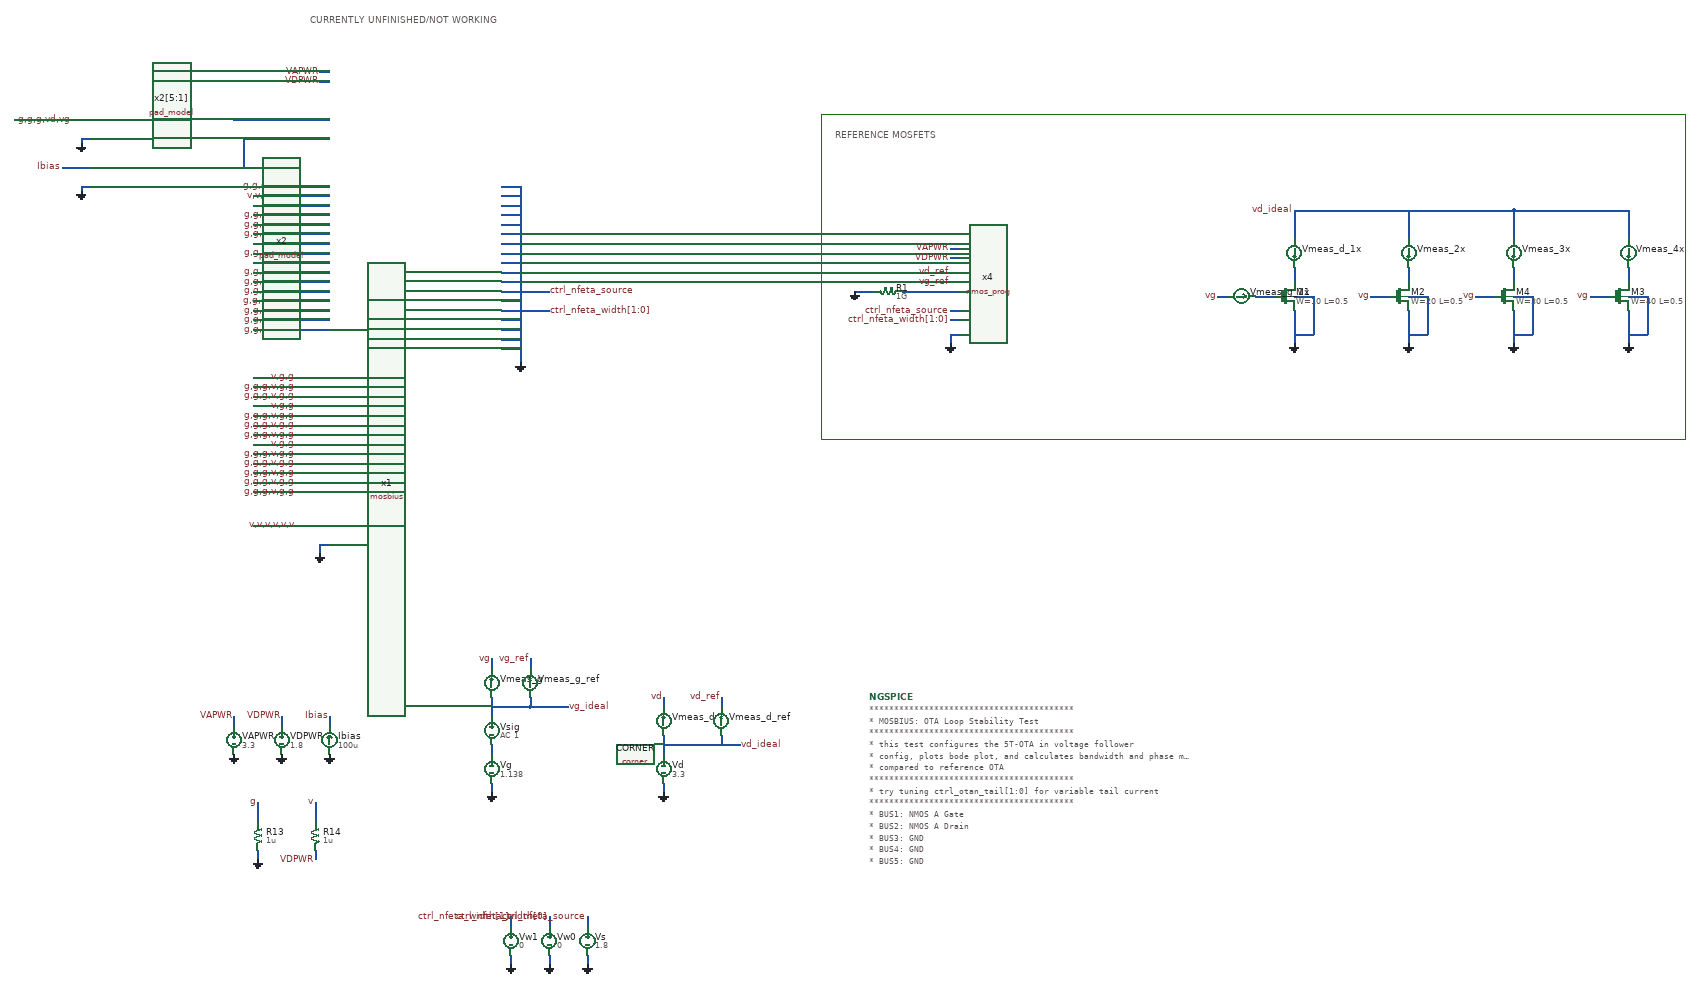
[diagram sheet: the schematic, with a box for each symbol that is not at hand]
v {xschem version=3.1.0 file_version=1.2
}
G {}
K {}
V {}
S {}
E {}
L 4 1330 -1160 1330 -480 {}
L 4 3140 -1160 3140 -480 {}
L 4 1330 -480 3140 -480 {}
L 4 1330 -1160 3140 -1160 {}
T {REFERENCE MOSFETS} 1360 -1130 0 0 0.4 0.4 {}
T {CURRENTLY UNFINISHED/NOT WORKING} 260 -1370 0 0 0.4 0.4 {}
N 100 100 100 120 {
lab=VAPWR}
N 200 100 200 120 {
lab=VDPWR}
N 280 -1230 300 -1230 {
lab=VDPWR}
N 280 -1250 300 -1250 {
lab=VAPWR}
N 280 -260 280 -240 {
lab=GND}
N 280 -260 300 -260 {
lab=GND}
N 300 100 300 120 {
lab=Ibias}
N 660 -970 700 -970 {
lab=GND}
N 660 -950 700 -950 {
lab=GND}
N 660 -930 700 -930 {
lab=GND}
N 660 -910 700 -910 {
lab=GND}
N 660 -890 700 -890 {
lab=GND}
N 660 -870 700 -870 {
lab=GND}
N 660 -850 700 -850 {
lab=GND}
N 660 -830 700 -830 {
lab=GND}
N 660 -810 700 -810 {
lab=GND}
N 660 -770 700 -770 {
lab=GND}
N 660 -730 700 -730 {
lab=GND}
N 660 -710 700 -710 {
lab=GND}
N 660 -690 700 -690 {
lab=GND}
N 660 -670 700 -670 {
lab=GND}
N 640 240 640 260 {
lab=GND}
N 660 -990 700 -990 {
lab=GND}
N 150 380 150 400 {
lab=GND}
N 150 280 150 320 {
lab=g}
N 270 280 270 320 {
lab=v}
N 270 380 270 400 {
lab=VDPWR}
N 140 -370 300 -370 {
lab=g,g,g,v,g,g}
N 140 -390 300 -390 {
lab=g,g,g,v,g,g}
N 140 -410 300 -410 {
lab=g,g,g,v,g,g}
N 140 -430 300 -430 {
lab=g,g,g,v,g,g}
N 140 -450 300 -450 {
lab=g,g,g,v,g,g}
N 140 -470 300 -470 {
lab=v,g,g}
N 140 -490 300 -490 {
lab=g,g,g,v,g,g}
N 140 -510 300 -510 {
lab=g,g,g,v,g,g}
N 140 -530 300 -530 {
lab=g,g,g,v,g,g}
N 140 -550 300 -550 {
lab=v,g,g}
N 140 -570 300 -570 {
lab=g,g,g,v,g,g}
N 140 -590 300 -590 {
lab=g,g,g,v,g,g}
N 140 -610 300 -610 {
lab=v,g,g}
N 140 -710 300 -710 {
lab=g,g,g,v,g,g}
N 140 -730 300 -730 {
lab=g,g,g,v,g,g}
N 140 -750 300 -750 {
lab=g,g,g,v,g,g}
N 140 -770 300 -770 {
lab=g,g,g,g,g,g}
N 140 -790 300 -790 {
lab=g,g,g,g,g,v}
N 140 -810 300 -810 {
lab=g,g,g,g,v,g}
N 140 -830 300 -830 {
lab=g,g,g,v,g,g}
N 140 -870 300 -870 {
lab=g,g,g,v,g,g}
N 140 -910 300 -910 {
lab=g,g,g,v,g,g}
N 140 -930 300 -930 {
lab=g,g,g,v,g,g}
N 140 -1010 300 -1010 {
lab=g,g,g,g,g,g}
N 140 -850 300 -850 {
lab=v,g,g}
N 140 -890 300 -890 {
lab=v,g,g}
N 140 -300 300 -300 {
lab=v,v,v,v,v,v}
N 140 -990 300 -990 {
lab=v,v,v,v,g,g}
N 140 -970 300 -970 {
lab=v,g,g}
N 140 -950 300 -950 {
lab=g,g,g,v,g,g}
N 1600 -860 1620 -860 {
lab=VDPWR}
N 1600 -880 1620 -880 {
lab=VAPWR}
N 1600 -700 1600 -680 {
lab=GND}
N 1600 -700 1620 -700 {
lab=GND}
N 1000 240 1000 260 {
lab=GND}
N 1600 -810 1620 -810 {
lab=vg_ref}
N 1600 -830 1620 -830 {
lab=vd_ref}
N 660 -1010 700 -1010 {
lab=GND}
N 700 -1010 700 -640 {
lab=GND}
N 660 -750 760 -750 {
lab=ctrl_nfeta_width[1:0]}
N 660 -790 760 -790 {
lab=ctrl_nfeta_source}
N 1600 -750 1620 -750 {
lab=ctrl_nfeta_source}
N 1600 -730 1620 -730 {
lab=ctrl_nfeta_width[1:0]}
N 680 600 680 620 {
lab=GND}
N 760 520 760 540 {
lab=ctrl_nfeta_width[0]}
N 760 600 760 620 {
lab=GND}
N 840 520 840 540 {
lab=ctrl_nfeta_source}
N 840 600 840 620 {
lab=GND}
N 680 520 680 540 {
lab=ctrl_nfeta_width[1]}
N 1000 140 1000 180 {
lab=vd_ideal}
N 1000 60 1000 80 {
lab=vd}
N 1000 160 1080 160 {
lab=vd_ideal}
N 1120 140 1120 160 {
lab=vd_ideal}
N 1120 60 1120 80 {
lab=vd_ref}
N 1500 -790 1620 -790 {
lab=#net1}
N 1400 -790 1440 -790 {
lab=GND}
N 2320 -750 2320 -680 {
lab=GND}
N 2320 -780 2360 -780 {
lab=GND}
N 2360 -780 2360 -700 {
lab=GND}
N 2320 -700 2360 -700 {
lab=GND}
N 2240 -780 2280 -780 {
lab=#net2}
N 2560 -750 2560 -680 {
lab=GND}
N 2560 -780 2600 -780 {
lab=GND}
N 2600 -780 2600 -700 {
lab=GND}
N 2560 -700 2600 -700 {
lab=GND}
N 2480 -780 2520 -780 {
lab=vg}
N 3020 -750 3020 -680 {
lab=GND}
N 3020 -780 3060 -780 {
lab=GND}
N 3060 -780 3060 -700 {
lab=GND}
N 3020 -700 3060 -700 {
lab=GND}
N 2940 -780 2980 -780 {
lab=vg}
N 3020 -840 3020 -810 {
lab=#net3}
N 2560 -840 2560 -810 {
lab=#net4}
N 2320 -840 2320 -810 {
lab=#net5}
N 2320 -960 2320 -900 {
lab=vd_ideal}
N 2320 -960 2780 -960 {
lab=vd_ideal}
N 3020 -960 3020 -900 {
lab=vd_ideal}
N 2560 -960 2560 -900 {
lab=vd_ideal}
N 2780 -960 3020 -960 {
lab=vd_ideal}
N 2780 -750 2780 -680 {
lab=GND}
N 2780 -780 2820 -780 {
lab=GND}
N 2820 -780 2820 -700 {
lab=GND}
N 2780 -700 2820 -700 {
lab=GND}
N 2700 -780 2740 -780 {
lab=vg}
N 2780 -840 2780 -810 {
lab=#net6}
N 2780 -960 2780 -900 {
lab=vd_ideal}
N 1080 160 1160 160 {
lab=vd_ideal}
N -360 -1150 -200 -1150 {
lab=g,g,g,vd,vg}
N 100 -1150 300 -1150 {
lab=#net7}
N -260 -1050 -200 -1050 {
lab=Ibias}
N 100 -1050 120 -1050 {
lab=#net8}
N 120 -1110 120 -1050 {
lab=#net8}
N 120 -1110 300 -1110 {
lab=#net8}
N -220 -1010 -220 -1000 {
lab=GND}
N -220 -1010 -200 -1010 {
lab=GND}
N -220 -1110 -220 -1100 {
lab=GND}
N -220 -1110 -200 -1110 {
lab=GND}
N 640 60 640 100 {
lab=vg_ideal}
N 640 160 640 180 {
lab=#net9}
N 640 -20 640 0 {
lab=vg}
N 640 80 720 80 {
lab=vg_ideal}
N 720 60 720 80 {
lab=vg_ideal}
N 720 -20 720 0 {
lab=vg_ref}
N 2160 -780 2180 -780 {
lab=vg}
N 720 80 800 80 {
lab=vg_ideal}
C {mosbius.sym} 300 -240 0 0 {name=x1}
C {devices/vsource.sym} 100 150 0 0 {name=VAPWR value=3.3}
C {devices/gnd.sym} 100 180 0 0 {name=l1 lab=GND}
C {devices/lab_pin.sym} 100 100 1 0 {name=p2 sig_type=std_logic lab=VAPWR}
C {devices/vsource.sym} 200 150 0 0 {name=VDPWR value=1.8}
C {devices/gnd.sym} 200 180 0 0 {name=l2 lab=GND}
C {devices/lab_pin.sym} 200 100 1 0 {name=p3 sig_type=std_logic lab=VDPWR}
C {devices/lab_pin.sym} 280 -1250 0 0 {name=p4 sig_type=std_logic lab=VAPWR}
C {devices/lab_pin.sym} 280 -1230 0 0 {name=p5 sig_type=std_logic lab=VDPWR}
C {devices/gnd.sym} 280 -240 0 0 {name=l3 lab=GND}
C {devices/isource.sym} 300 150 2 1 {name=Ibias value=100u}
C {devices/gnd.sym} 300 180 0 0 {name=l4 lab=GND}
C {devices/lab_pin.sym} 300 100 1 0 {name=p1 sig_type=std_logic lab=Ibias}
C {devices/gnd.sym} 700 -640 0 0 {name=l5 lab=GND}
C {devices/vsource.sym} 1000 210 0 0 {name=Vd value=3.3}
C {devices/vsource.sym} 640 210 0 0 {name=Vg value=1.138}
C {devices/gnd.sym} 640 260 0 0 {name=l9 lab=GND}
C {devices/lab_pin.sym} 1000 60 1 0 {name=p10 sig_type=std_logic lab=vd}
C {sky130_fd_pr/corner.sym} 1480 -170 0 0 {name=CORNER only_toplevel=true corner=tt}
C {devices/code_shown.sym} 1430 60 0 0 {name=NGSPICE only_toplevel=true value=
"
*****************************************
* MOSBIUS: OTA Loop Stability Test
*****************************************
* this test configures the 5T-OTA in voltage follower
* config, plots bode plot, and calculates bandwidth and phase margin, 
* compared to reference OTA
*****************************************
* try tuning ctrl_otan_tail[1:0] for variable tail current
*****************************************
* BUS1: NMOS A Gate
* BUS2: NMOS A Drain
* BUS3: GND
* BUS4: GND
* BUS5: GND
* BUS6: GND
*****************************************
.option rshunt=1e11
.control
   save all
   set temp = 27
   alter Vw1=0
   alter Vw0=0
   ac dec 51 1Meg 100G
   plot i(vmeas_g) i(vmeas_d) xlog ylog
   plot i(vmeas_g_ref) i(vmeas_d_ref) xlog ylog
   plot i(vmeas_g_1x) i(vmeas_d_1x) xlog ylog
.endc
"}
C {devices/lab_wire.sym} 230 -370 0 0 {name=p16 sig_type=std_logic lab=g,g,g,v,g,g}
C {devices/gnd.sym} 150 400 0 0 {name=l10 lab=GND}
C {devices/res.sym} 150 350 0 0 {name=R13
value=1u
footprint=1206
device=resistor
m=1}
C {devices/lab_pin.sym} 150 280 0 0 {name=p17 sig_type=std_logic lab=g}
C {devices/res.sym} 270 350 0 0 {name=R14
value=1u
footprint=1206
device=resistor
m=1}
C {devices/lab_pin.sym} 270 400 3 0 {name=p18 sig_type=std_logic lab=VDPWR}
C {devices/lab_pin.sym} 270 280 0 0 {name=p19 sig_type=std_logic lab=v}
C {devices/lab_wire.sym} 230 -390 0 0 {name=p20 sig_type=std_logic lab=g,g,g,v,g,g}
C {devices/lab_wire.sym} 230 -410 0 0 {name=p21 sig_type=std_logic lab=g,g,g,v,g,g}
C {devices/lab_wire.sym} 230 -430 0 0 {name=p22 sig_type=std_logic lab=g,g,g,v,g,g}
C {devices/lab_wire.sym} 230 -450 0 0 {name=p24 sig_type=std_logic lab=g,g,g,v,g,g}
C {devices/lab_wire.sym} 230 -470 0 0 {name=p27 sig_type=std_logic lab=v,g,g}
C {devices/lab_wire.sym} 230 -490 0 0 {name=p39 sig_type=std_logic lab=g,g,g,v,g,g}
C {devices/lab_wire.sym} 230 -510 0 0 {name=p40 sig_type=std_logic lab=g,g,g,v,g,g}
C {devices/lab_wire.sym} 230 -530 0 0 {name=p41 sig_type=std_logic lab=g,g,g,v,g,g}
C {devices/lab_wire.sym} 230 -550 0 0 {name=p42 sig_type=std_logic lab=v,g,g}
C {devices/lab_wire.sym} 230 -570 0 0 {name=p43 sig_type=std_logic lab=g,g,g,v,g,g}
C {devices/lab_wire.sym} 230 -590 0 0 {name=p44 sig_type=std_logic lab=g,g,g,v,g,g}
C {devices/lab_wire.sym} 230 -610 0 0 {name=p45 sig_type=std_logic lab=v,g,g}
C {devices/lab_wire.sym} 230 -710 0 0 {name=p46 sig_type=std_logic lab=g,g,g,v,g,g}
C {devices/lab_wire.sym} 230 -730 0 0 {name=p47 sig_type=std_logic lab=g,g,g,v,g,g}
C {devices/lab_wire.sym} 230 -750 0 0 {name=p48 sig_type=std_logic lab=g,g,g,v,g,g}
C {devices/lab_wire.sym} 230 -770 0 0 {name=p49 sig_type=std_logic lab=g,g,g,g,g,g}
C {devices/lab_wire.sym} 230 -790 0 0 {name=p50 sig_type=std_logic lab=g,g,g,g,g,v}
C {devices/lab_wire.sym} 230 -810 0 0 {name=p51 sig_type=std_logic lab=g,g,g,g,v,g}
C {devices/lab_wire.sym} 230 -870 0 0 {name=p53 sig_type=std_logic lab=g,g,g,v,g,g}
C {devices/lab_wire.sym} 230 -910 0 0 {name=p54 sig_type=std_logic lab=g,g,g,v,g,g}
C {devices/lab_wire.sym} 230 -930 0 0 {name=p55 sig_type=std_logic lab=g,g,g,v,g,g}
C {devices/lab_wire.sym} 230 -1010 0 0 {name=p56 sig_type=std_logic lab=g,g,g,g,g,g}
C {devices/lab_wire.sym} 230 -850 0 0 {name=p57 sig_type=std_logic lab=v,g,g}
C {devices/lab_wire.sym} 230 -890 0 0 {name=p58 sig_type=std_logic lab=v,g,g}
C {devices/lab_wire.sym} 230 -300 0 0 {name=p25 sig_type=std_logic lab=v,v,v,v,v,v}
C {devices/lab_wire.sym} 230 -990 0 0 {name=p11 sig_type=std_logic lab=v,v,v,v,g,g}
C {devices/lab_wire.sym} 230 -970 0 0 {name=p15 sig_type=std_logic lab=v,g,g}
C {devices/lab_wire.sym} 230 -950 0 0 {name=p7 sig_type=std_logic lab=g,g,g,v,g,g}
C {devices/lab_wire.sym} -240 -1150 0 0 {name=p9 sig_type=std_logic lab=g,g,g,vd,vg}
C {nmos_prog.sym} 1390 -800 0 0 {name=x4}
C {devices/lab_pin.sym} 1600 -880 0 0 {name=p12 sig_type=std_logic lab=VAPWR}
C {devices/lab_pin.sym} 1600 -860 0 0 {name=p13 sig_type=std_logic lab=VDPWR}
C {devices/gnd.sym} 1600 -680 0 0 {name=l6 lab=GND}
C {devices/gnd.sym} 1000 260 0 0 {name=l7 lab=GND}
C {devices/lab_pin.sym} 1600 -830 0 0 {name=p23 sig_type=std_logic lab=vd_ref}
C {devices/lab_pin.sym} 1600 -810 0 0 {name=p26 sig_type=std_logic lab=vg_ref}
C {devices/lab_wire.sym} 230 -830 0 0 {name=p14 sig_type=std_logic lab=g,g,g,v,g,g}
C {devices/lab_pin.sym} 760 -790 0 1 {name=p28 sig_type=std_logic lab=ctrl_nfeta_source}
C {devices/lab_pin.sym} 760 -750 0 1 {name=p29 sig_type=std_logic lab=ctrl_nfeta_width[1:0]}
C {devices/lab_pin.sym} 1600 -750 0 0 {name=p30 sig_type=std_logic lab=ctrl_nfeta_source}
C {devices/lab_pin.sym} 1600 -730 0 0 {name=p31 sig_type=std_logic lab=ctrl_nfeta_width[1:0]}
C {devices/vsource.sym} 760 570 0 0 {name=Vw0 value=0}
C {devices/vsource.sym} 680 570 0 0 {name=Vw1 value=0}
C {devices/gnd.sym} 680 620 0 0 {name=l8 lab=GND}
C {devices/lab_pin.sym} 680 520 1 0 {name=p33 sig_type=std_logic lab=ctrl_nfeta_width[1]}
C {devices/gnd.sym} 760 620 0 0 {name=l11 lab=GND}
C {devices/vsource.sym} 840 570 0 0 {name=Vs value=1.8}
C {devices/gnd.sym} 840 620 0 0 {name=l12 lab=GND}
C {devices/lab_pin.sym} 760 520 1 0 {name=p32 sig_type=std_logic lab=ctrl_nfeta_width[0]}
C {devices/lab_pin.sym} 840 520 1 0 {name=p34 sig_type=std_logic lab=ctrl_nfeta_source}
C {devices/ammeter.sym} 1000 110 2 0 {name=Vmeas_d}
C {devices/ammeter.sym} 1120 110 2 0 {name=Vmeas_d_ref}
C {devices/lab_pin.sym} 1120 60 1 0 {name=p35 sig_type=std_logic lab=vd_ref}
C {devices/res.sym} 1470 -790 1 0 {name=R1
value=1G
footprint=1206
device=resistor
m=1}
C {devices/gnd.sym} 1400 -790 1 0 {name=l13 lab=GND}
C {sky130_fd_pr/nfet_g5v0d10v5.sym} 2300 -780 0 0 {name=M1
L=0.5
W=10
nf=2
mult=1
ad="'int((nf+1)/2) * W/nf * 0.29'" 
pd="'2*int((nf+1)/2) * (W/nf + 0.29)'"
as="'int((nf+2)/2) * W/nf * 0.29'" 
ps="'2*int((nf+2)/2) * (W/nf + 0.29)'"
nrd="'0.29 / W'" nrs="'0.29 / W'"
sa=0 sb=0 sd=0
model=nfet_g5v0d10v5
spiceprefix=X
}
C {devices/gnd.sym} 2320 -680 0 0 {name=l14 lab=GND}
C {devices/lab_pin.sym} 2160 -780 2 1 {name=p36 sig_type=std_logic lab=vg}
C {sky130_fd_pr/nfet_g5v0d10v5.sym} 2540 -780 0 0 {name=M2
L=0.5
W=20
nf=4
mult=1
ad="'int((nf+1)/2) * W/nf * 0.29'" 
pd="'2*int((nf+1)/2) * (W/nf + 0.29)'"
as="'int((nf+2)/2) * W/nf * 0.29'" 
ps="'2*int((nf+2)/2) * (W/nf + 0.29)'"
nrd="'0.29 / W'" nrs="'0.29 / W'"
sa=0 sb=0 sd=0
model=nfet_g5v0d10v5
spiceprefix=X
}
C {devices/gnd.sym} 2560 -680 0 0 {name=l15 lab=GND}
C {devices/lab_pin.sym} 2480 -780 2 1 {name=p37 sig_type=std_logic lab=vg}
C {sky130_fd_pr/nfet_g5v0d10v5.sym} 3000 -780 0 0 {name=M3
L=0.5
W=40
nf=8
mult=1
ad="'int((nf+1)/2) * W/nf * 0.29'" 
pd="'2*int((nf+1)/2) * (W/nf + 0.29)'"
as="'int((nf+2)/2) * W/nf * 0.29'" 
ps="'2*int((nf+2)/2) * (W/nf + 0.29)'"
nrd="'0.29 / W'" nrs="'0.29 / W'"
sa=0 sb=0 sd=0
model=nfet_g5v0d10v5
spiceprefix=X
}
C {devices/gnd.sym} 3020 -680 0 0 {name=l16 lab=GND}
C {devices/lab_pin.sym} 2940 -780 2 1 {name=p38 sig_type=std_logic lab=vg}
C {devices/ammeter.sym} 2320 -870 0 0 {name=Vmeas_d_1x}
C {devices/ammeter.sym} 2560 -870 0 0 {name=Vmeas_2x}
C {devices/ammeter.sym} 3020 -870 0 0 {name=Vmeas_4x}
C {devices/lab_pin.sym} 2320 -960 2 1 {name=p52 sig_type=std_logic lab=vd_ideal}
C {sky130_fd_pr/nfet_g5v0d10v5.sym} 2760 -780 0 0 {name=M4
L=0.5
W=30
nf=6
mult=1
ad="'int((nf+1)/2) * W/nf * 0.29'" 
pd="'2*int((nf+1)/2) * (W/nf + 0.29)'"
as="'int((nf+2)/2) * W/nf * 0.29'" 
ps="'2*int((nf+2)/2) * (W/nf + 0.29)'"
nrd="'0.29 / W'" nrs="'0.29 / W'"
sa=0 sb=0 sd=0
model=nfet_g5v0d10v5
spiceprefix=X
}
C {devices/gnd.sym} 2780 -680 0 0 {name=l17 lab=GND}
C {devices/lab_pin.sym} 2700 -780 2 1 {name=p59 sig_type=std_logic lab=vg}
C {devices/ammeter.sym} 2780 -870 0 0 {name=Vmeas_3x}
C {devices/lab_pin.sym} 1160 160 2 0 {name=p60 sig_type=std_logic lab=vd_ideal}
C {pad_model.sym} -50 -1130 0 0 {name=x2[5:1]}
C {pad_model.sym} -50 -1030 0 0 {name=x2}
C {devices/lab_pin.sym} -260 -1050 0 0 {name=p62 sig_type=std_logic lab=Ibias}
C {devices/gnd.sym} -220 -1100 0 0 {name=l18 lab=GND}
C {devices/gnd.sym} -220 -1000 0 0 {name=l19 lab=GND}
C {devices/vsource.sym} 640 130 0 0 {name=Vsig value="AC 1"}
C {devices/lab_pin.sym} 640 -20 1 0 {name=p6 sig_type=std_logic lab=vg}
C {devices/ammeter.sym} 640 30 2 0 {name=Vmeas_g}
C {devices/ammeter.sym} 720 30 2 0 {name=Vmeas_g_ref}
C {devices/lab_pin.sym} 720 -20 1 0 {name=p8 sig_type=std_logic lab=vg_ref}
C {devices/ammeter.sym} 2210 -780 3 0 {name=Vmeas_g_1x}
C {devices/lab_pin.sym} 800 80 2 0 {name=p61 sig_type=std_logic lab=vg_ideal}
